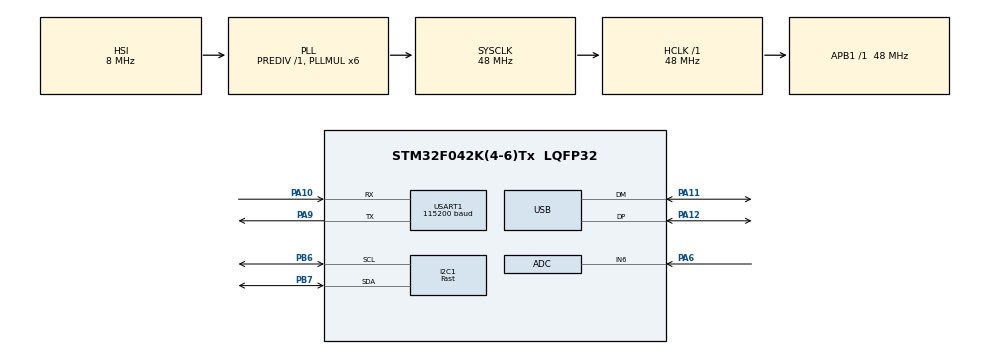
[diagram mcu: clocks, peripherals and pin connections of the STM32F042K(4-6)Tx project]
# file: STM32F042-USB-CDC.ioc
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Dma.I2C1_RX.0.Direction=DMA_PERIPH_TO_MEMORY
Dma.I2C1_RX.0.Instance=DMA1_Channel3
Dma.I2C1_RX.0.MemDataAlignment=DMA_MDATAALIGN_BYTE
Dma.I2C1_RX.0.MemInc=DMA_MINC_ENABLE
Dma.I2C1_RX.0.Mode=DMA_NORMAL
Dma.I2C1_RX.0.PeriphDataAlignment=DMA_PDATAALIGN_BYTE
Dma.I2C1_RX.0.PeriphInc=DMA_PINC_DISABLE
Dma.I2C1_RX.0.Priority=DMA_PRIORITY_MEDIUM
Dma.I2C1_TX.1.Direction=DMA_MEMORY_TO_PERIPH
Dma.I2C1_TX.1.Instance=DMA1_Channel2
Dma.I2C1_TX.1.MemDataAlignment=DMA_MDATAALIGN_BYTE
Dma.I2C1_TX.1.MemInc=DMA_MINC_ENABLE
Dma.I2C1_TX.1.Mode=DMA_NORMAL
Dma.I2C1_TX.1.PeriphDataAlignment=DMA_PDATAALIGN_BYTE
Dma.I2C1_TX.1.PeriphInc=DMA_PINC_DISABLE
Dma.I2C1_TX.1.Priority=DMA_PRIORITY_MEDIUM
Dma.Request0=I2C1_RX
Dma.Request1=I2C1_TX
I2C1.I2C_Speed_Mode=I2C_Fast
I2C1.Speed=400
I2C1.Timing=0x2010091A
IWDG.Prescaler=IWDG_PRESCALER_32
Mcu.Family=STM32F0
Mcu.Name=STM32F042K(4-6)Tx
Mcu.Package=LQFP32
NVIC.DMA1_Channel2_3_IRQn=true\:0\:0\:false\:false\:true\:false
NVIC.I2C1_IRQn=true\:0\:0\:false\:false\:true\:true
NVIC.USART1_IRQn=true\:0\:0\:false\:false\:true\:true
NVIC.USB_IRQn=true\:0\:0\:false\:false\:true\:false
PA10.Mode=Asynchronous
PA10.Signal=USART1_RX
PA11.Mode=Device
PA11.Signal=USB_DM
PA12.Mode=Device
PA12.Signal=USB_DP
PA6.Mode=IN6
PA6.Signal=ADC_IN6
PA9.Mode=Asynchronous
PA9.Signal=USART1_TX
PB6.GPIO_FM8=__NULL
PB6.Mode=I2C
PB6.Signal=I2C1_SCL
PB7.GPIO_FM7=__NULL
PB7.Mode=I2C
PB7.Signal=I2C1_SDA
ProjectManager.HeapSize=0x200
ProjectManager.StackSize=0x400
ProjectManager.TargetToolchain=MDK-ARM V5
RCC.AHBFreq_Value=48000000
RCC.APB1Freq_Value=48000000
RCC.APB1TimFreq_Value=48000000
RCC.HCLKFreq_Value=48000000
RCC.I2c1ClockSelection=RCC_I2C1CLKSOURCE_SYSCLK
RCC.PLLMUL=RCC_PLL_MUL6
RCC.SYSCLKFreq_VALUE=48000000
RCC.SYSCLKSource=RCC_SYSCLKSOURCE_PLLCLK
RCC.USBFreq_Value=48000000
USART1.BaudRate=115200
USART1.VirtualMode-Asynchronous=VM_ASYNC
USB_DEVICE.APP_RX_DATA_SIZE=512
USB_DEVICE.APP_TX_DATA_SIZE=512
USB_DEVICE.CLASS_NAME_FS=CDC
USB_DEVICE.CONFIGURATION_STRING_CDC_FS=40
USB_DEVICE.MANUFACTURER_STRING=CANAAN
USB_DEVICE.PID_CDC_FS=0x33F2
USB_DEVICE.PRODUCT_STRING_CDC_FS=USB2IIC Converter
USB_DEVICE.SERIALNUMBER_STRING_CDC_FS=20180329
USB_DEVICE.USBD_SELF_POWERED=0
USB_DEVICE.VID=0x29F1
USB_DEVICE.VirtualMode=Cdc
USB_DEVICE.VirtualModeFS=Cdc_FS
VP_IWDG_VS_IWDG.Mode=IWDG_Activate
VP_USB_DEVICE_VS_USB_DEVICE_CDC_FS.Mode=CDC_FS
board=STM32F042-USB-CDC

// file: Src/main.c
/**
  ******************************************************************************
  * @file           : main.c
  * @brief          : Main program body
  ******************************************************************************
  * This notice applies to any and all portions of this file
  * that are not between comment pairs USER CODE BEGIN and
  * USER CODE END. Other portions of this file, whether
  * inserted by the user or by software development tools
  * are owned by their respective copyright owners.
  *
  * Copyright (c) 2018 STMicroelectronics International N.V.
  * All rights reserved.
  *
  * Redistribution and use in source and binary forms, with or without
  * modification, are permitted, provided that the following conditions are met:
  *
  * 1. Redistribution of source code must retain the above copyright notice,
  *    this list of conditions and the following disclaimer.
  * 2. Redistributions in binary form must reproduce the above copyright notice,
  *    this list of conditions and the following disclaimer in the documentation
  *    and/or other materials provided with the distribution.
  * 3. Neither the name of STMicroelectronics nor the names of other
  *    contributors to this software may be used to endorse or promote products
  *    derived from this software without specific written permission.
  * 4. This software, including modifications and/or derivative works of this
  *    software, must execute solely and exclusively on microcontroller or
  *    microprocessor devices manufactured by or for STMicroelectronics.
  * 5. Redistribution and use of this software other than as permitted under
  *    this license is void and will automatically terminate your rights under
  *    this license.
  *
  * THIS SOFTWARE IS PROVIDED BY STMICROELECTRONICS AND CONTRIBUTORS "AS IS"
  * AND ANY EXPRESS, IMPLIED OR STATUTORY WARRANTIES, INCLUDING, BUT NOT
  * LIMITED TO, THE IMPLIED WARRANTIES OF MERCHANTABILITY, FITNESS FOR A
  * PARTICULAR PURPOSE AND NON-INFRINGEMENT OF THIRD PARTY INTELLECTUAL PROPERTY
  * RIGHTS ARE DISCLAIMED TO THE FULLEST EXTENT PERMITTED BY LAW. IN NO EVENT
  * SHALL STMICROELECTRONICS OR CONTRIBUTORS BE LIABLE FOR ANY DIRECT, INDIRECT,
  * INCIDENTAL, SPECIAL, EXEMPLARY, OR CONSEQUENTIAL DAMAGES (INCLUDING, BUT NOT
  * LIMITED TO, PROCUREMENT OF SUBSTITUTE GOODS OR SERVICES; LOSS OF USE, DATA,
  * OR PROFITS; OR BUSINESS INTERRUPTION) HOWEVER CAUSED AND ON ANY THEORY OF
  * LIABILITY, WHETHER IN CONTRACT, STRICT LIABILITY, OR TORT (INCLUDING
  * NEGLIGENCE OR OTHERWISE) ARISING IN ANY WAY OUT OF THE USE OF THIS SOFTWARE,
  * EVEN IF ADVISED OF THE POSSIBILITY OF SUCH DAMAGE.
  *
  ******************************************************************************
  */
#include "main.h"
#include "stm32f0xx_hal.h"
#include "usb_device.h"

/* USER CODE BEGIN Includes */
#include "usbd_cdc_if.h"
/* USER CODE END Includes */

ADC_HandleTypeDef hadc;

I2C_HandleTypeDef hi2c1;
DMA_HandleTypeDef hdma_i2c1_rx;
DMA_HandleTypeDef hdma_i2c1_tx;

IWDG_HandleTypeDef hiwdg;

UART_HandleTypeDef huart1;

/* USER CODE BEGIN PV */
/* Private variables ---------------------------------------------------------*/

/* USER CODE END PV */

void SystemClock_Config(void);
static void MX_GPIO_Init(void);
static void MX_DMA_Init(void);
static void MX_I2C1_Init(void);
static void MX_IWDG_Init(void);
static void MX_ADC_Init(void);
static void MX_USART1_UART_Init(void);

/* USER CODE BEGIN PFP */
/* Private function prototypes -----------------------------------------------*/

/* USER CODE END PFP */

int main(void)
{

  /* MCU Configuration----------------------------------------------------------*/

  /* Reset of all peripherals, Initializes the Flash interface and the Systick. */
  HAL_Init();

  /* Configure the system clock */
  SystemClock_Config();

  /* Initialize all configured peripherals */
  MX_GPIO_Init();
  MX_DMA_Init();
  MX_I2C1_Init();
  MX_IWDG_Init();
  HAL_Delay(1000);
  MX_USB_DEVICE_Init();
  MX_ADC_Init();
  MX_USART1_UART_Init();
  HAL_GPIO_WritePin(GPIOF, GPIO_PIN_0, GPIO_PIN_RESET);
  HAL_GPIO_WritePin(GPIOF, GPIO_PIN_1, GPIO_PIN_SET);
  HAL_IWDG_Refresh(&hiwdg);

  /* Infinite loop */
  while (1)
  {
    CDC_I2C_Process(&hi2c1, &hiwdg);
  }

}

void SystemClock_Config(void)
{

  RCC_OscInitTypeDef RCC_OscInitStruct;
  RCC_ClkInitTypeDef RCC_ClkInitStruct;
  RCC_PeriphCLKInitTypeDef PeriphClkInit;

    /**Initializes the CPU, AHB and APB busses clocks
    */
  RCC_OscInitStruct.OscillatorType = RCC_OSCILLATORTYPE_HSI|RCC_OSCILLATORTYPE_HSI14
                              |RCC_OSCILLATORTYPE_HSI48|RCC_OSCILLATORTYPE_LSI;
  RCC_OscInitStruct.HSIState = RCC_HSI_ON;
  RCC_OscInitStruct.HSI48State = RCC_HSI48_ON;
  RCC_OscInitStruct.HSI14State = RCC_HSI14_ON;
  RCC_OscInitStruct.HSICalibrationValue = 16;
  RCC_OscInitStruct.HSI14CalibrationValue = 16;
  RCC_OscInitStruct.LSIState = RCC_LSI_ON;
  RCC_OscInitStruct.PLL.PLLState = RCC_PLL_ON;
  RCC_OscInitStruct.PLL.PLLSource = RCC_PLLSOURCE_HSI;
  RCC_OscInitStruct.PLL.PLLMUL = RCC_PLL_MUL6;
  RCC_OscInitStruct.PLL.PREDIV = RCC_PREDIV_DIV1;
  if (HAL_RCC_OscConfig(&RCC_OscInitStruct) != HAL_OK)
  {
    _Error_Handler(__FILE__, __LINE__);
  }

    /**Initializes the CPU, AHB and APB busses clocks
    */
  RCC_ClkInitStruct.ClockType = RCC_CLOCKTYPE_HCLK|RCC_CLOCKTYPE_SYSCLK
                              |RCC_CLOCKTYPE_PCLK1;
  RCC_ClkInitStruct.SYSCLKSource = RCC_SYSCLKSOURCE_PLLCLK;
  RCC_ClkInitStruct.AHBCLKDivider = RCC_SYSCLK_DIV1;
  RCC_ClkInitStruct.APB1CLKDivider = RCC_HCLK_DIV1;

  if (HAL_RCC_ClockConfig(&RCC_ClkInitStruct, FLASH_LATENCY_1) != HAL_OK)
  {
    _Error_Handler(__FILE__, __LINE__);
  }

  PeriphClkInit.PeriphClockSelection = RCC_PERIPHCLK_USB|RCC_PERIPHCLK_USART1
                              |RCC_PERIPHCLK_I2C1;
  PeriphClkInit.Usart1ClockSelection = RCC_USART1CLKSOURCE_PCLK1;
  PeriphClkInit.I2c1ClockSelection = RCC_I2C1CLKSOURCE_SYSCLK;
  PeriphClkInit.UsbClockSelection = RCC_USBCLKSOURCE_HSI48;

  if (HAL_RCCEx_PeriphCLKConfig(&PeriphClkInit) != HAL_OK)
  {
    _Error_Handler(__FILE__, __LINE__);
  }

    /**Configure the Systick interrupt time
    */
  HAL_SYSTICK_Config(HAL_RCC_GetHCLKFreq()/1000);

    /**Configure the Systick
    */
  HAL_SYSTICK_CLKSourceConfig(SYSTICK_CLKSOURCE_HCLK);

  /* SysTick_IRQn interrupt configuration */
  HAL_NVIC_SetPriority(SysTick_IRQn, 0, 0);
}

/* ADC init function */
static void MX_ADC_Init(void)
{

  ADC_ChannelConfTypeDef sConfig;

    /**Configure the global features of the ADC (Clock, Resolution, Data Alignment and number of conversion)
    */
  hadc.Instance = ADC1;
  hadc.Init.ClockPrescaler = ADC_CLOCK_ASYNC_DIV1;
  hadc.Init.Resolution = ADC_RESOLUTION_12B;
  hadc.Init.DataAlign = ADC_DATAALIGN_RIGHT;
  hadc.Init.ScanConvMode = ADC_SCAN_DIRECTION_FORWARD;
  hadc.Init.EOCSelection = ADC_EOC_SINGLE_CONV;
  hadc.Init.LowPowerAutoWait = DISABLE;
  hadc.Init.LowPowerAutoPowerOff = DISABLE;
  hadc.Init.ContinuousConvMode = DISABLE;
  hadc.Init.DiscontinuousConvMode = DISABLE;
  hadc.Init.ExternalTrigConv = ADC_SOFTWARE_START;
  hadc.Init.ExternalTrigConvEdge = ADC_EXTERNALTRIGCONVEDGE_NONE;
  hadc.Init.DMAContinuousRequests = DISABLE;
  hadc.Init.Overrun = ADC_OVR_DATA_PRESERVED;
  if (HAL_ADC_Init(&hadc) != HAL_OK)
  {
    _Error_Handler(__FILE__, __LINE__);
  }

    /**Configure for the selected ADC regular channel to be converted.
    */
  sConfig.Channel = ADC_CHANNEL_6;
  sConfig.Rank = ADC_RANK_CHANNEL_NUMBER;
  sConfig.SamplingTime = ADC_SAMPLETIME_1CYCLE_5;
  if (HAL_ADC_ConfigChannel(&hadc, &sConfig) != HAL_OK)
  {
    _Error_Handler(__FILE__, __LINE__);
  }

}

/* I2C1 init function */
static void MX_I2C1_Init(void)
{

  hi2c1.Instance = I2C1;
  hi2c1.Init.Timing = 0x2010091A;
  hi2c1.Init.OwnAddress1 = 0;
  hi2c1.Init.AddressingMode = I2C_ADDRESSINGMODE_7BIT;
  hi2c1.Init.DualAddressMode = I2C_DUALADDRESS_DISABLE;
  hi2c1.Init.OwnAddress2 = 0;
  hi2c1.Init.OwnAddress2Masks = I2C_OA2_NOMASK;
  hi2c1.Init.GeneralCallMode = I2C_GENERALCALL_DISABLE;
  hi2c1.Init.NoStretchMode = I2C_NOSTRETCH_DISABLE;
  if (HAL_I2C_Init(&hi2c1) != HAL_OK)
  {
    _Error_Handler(__FILE__, __LINE__);
  }

    /**Configure Analogue filter
    */
  if (HAL_I2CEx_ConfigAnalogFilter(&hi2c1, I2C_ANALOGFILTER_ENABLE) != HAL_OK)
  {
    _Error_Handler(__FILE__, __LINE__);
  }

    /**Configure Digital filter
    */
  if (HAL_I2CEx_ConfigDigitalFilter(&hi2c1, 0) != HAL_OK)
  {
    _Error_Handler(__FILE__, __LINE__);
  }

}

/* IWDG init function */
static void MX_IWDG_Init(void)
{

  hiwdg.Instance = IWDG;
  hiwdg.Init.Prescaler = IWDG_PRESCALER_64;
  hiwdg.Init.Window = 4095;
  hiwdg.Init.Reload = 4095;
  if (HAL_IWDG_Init(&hiwdg) != HAL_OK)
  {
    _Error_Handler(__FILE__, __LINE__);
  }
}

/* USART1 init function */
static void MX_USART1_UART_Init(void)
{

  huart1.Instance = USART1;
  huart1.Init.BaudRate = 115200;
  huart1.Init.WordLength = UART_WORDLENGTH_7B;
  huart1.Init.StopBits = UART_STOPBITS_1;
  huart1.Init.Parity = UART_PARITY_NONE;
  huart1.Init.Mode = UART_MODE_TX_RX;
  huart1.Init.HwFlowCtl = UART_HWCONTROL_NONE;
  huart1.Init.OverSampling = UART_OVERSAMPLING_16;
  huart1.Init.OneBitSampling = UART_ONE_BIT_SAMPLE_DISABLE;
  huart1.AdvancedInit.AdvFeatureInit = UART_ADVFEATURE_NO_INIT;
  if (HAL_UART_Init(&huart1) != HAL_OK)
  {
    _Error_Handler(__FILE__, __LINE__);
  }

}

static void MX_DMA_Init(void)
{
  /* DMA controller clock enable */
  __HAL_RCC_DMA1_CLK_ENABLE();

  /* DMA interrupt init */
  /* DMA1_Channel2_3_IRQn interrupt configuration */
  HAL_NVIC_SetPriority(DMA1_Channel2_3_IRQn, 0, 0);
  HAL_NVIC_EnableIRQ(DMA1_Channel2_3_IRQn);

}

/** Pinout Configuration
*/
static void MX_GPIO_Init(void)
{

  /* GPIO Ports Clock Enable */
  __HAL_RCC_GPIOA_CLK_ENABLE();
  __HAL_RCC_GPIOB_CLK_ENABLE();
  __HAL_RCC_GPIOF_CLK_ENABLE();

  GPIO_InitTypeDef GPIO_InitStruct;
  GPIO_InitStruct.Pin = GPIO_PIN_0|GPIO_PIN_1;
  GPIO_InitStruct.Mode = GPIO_MODE_OUTPUT_PP;
  GPIO_InitStruct.Speed = GPIO_SPEED_FREQ_LOW;
  HAL_GPIO_Init(GPIOF, &GPIO_InitStruct);
  HAL_GPIO_WritePin(GPIOF, GPIO_PIN_0, GPIO_PIN_SET);
  HAL_GPIO_WritePin(GPIOF, GPIO_PIN_1, GPIO_PIN_SET);
}

void _Error_Handler(char *file, int line)
{
  while(1)
  {
  }
}

/************************ (C) COPYRIGHT STMicroelectronics *****END OF FILE****/
